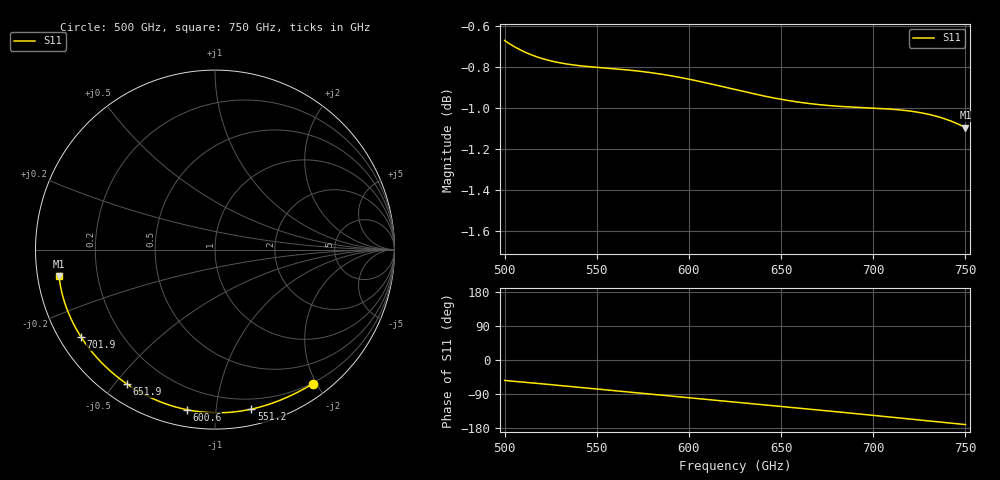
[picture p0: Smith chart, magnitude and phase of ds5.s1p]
!Created with skrf (http://scikit-rf.org).
# GHz S RI R 50.0
!freq ReS11 ImS11
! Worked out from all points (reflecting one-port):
!   401 points, 500 GHz to 750 GHz, reference 50 ohm
!   lowest |S11| = -1.1 dB at 750 GHz (marker M1), VSWR 15.87, Z = 3.17 - j4.19 ohm
!   phase of S11 starts at -54 deg and turns -116 deg over the sweep
!   S11 on the Smith chart (normalised r, x): 500 GHz: 0.19, -1.95; 551.2 GHz: 0.12, -1.25; 600.6 GHz: 0.08, -0.84; 651.9 GHz: 0.07, -0.54; 701.9 GHz: 0.06, -0.30; 750 GHz: 0.06, -0.08
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500  0.5441 -0.7487
501.25  0.5367 -0.753
513.125  0.4639 -0.7929
522.5  0.4033 -0.822
531.25  0.3444 -0.8464
541.25  0.2748 -0.8701
551.25  0.2031 -0.8887
562.5  0.1209 -0.9026
570.625  0.0611 -0.9079
578.125  0.00581 -0.9091
585.625  -0.0492 -0.9068
593.75  -0.1081 -0.9003
600.625  -0.1573 -0.8918
612.5  -0.2403 -0.8706
625  -0.3246 -0.8399
638.125  -0.4091 -0.799
651.875  -0.493 -0.7472
656.25  -0.5186 -0.7289
671.875  -0.6053 -0.6562
687.5  -0.6838 -0.5723
701.875  -0.747 -0.4857
710.625  -0.7804 -0.4289
718.75  -0.8075 -0.3736
726.875  -0.8304 -0.3164
735  -0.8486 -0.2576
741.875  -0.8602 -0.2071
748.75  -0.8681 -0.1564
750  -0.8691 -0.1471
